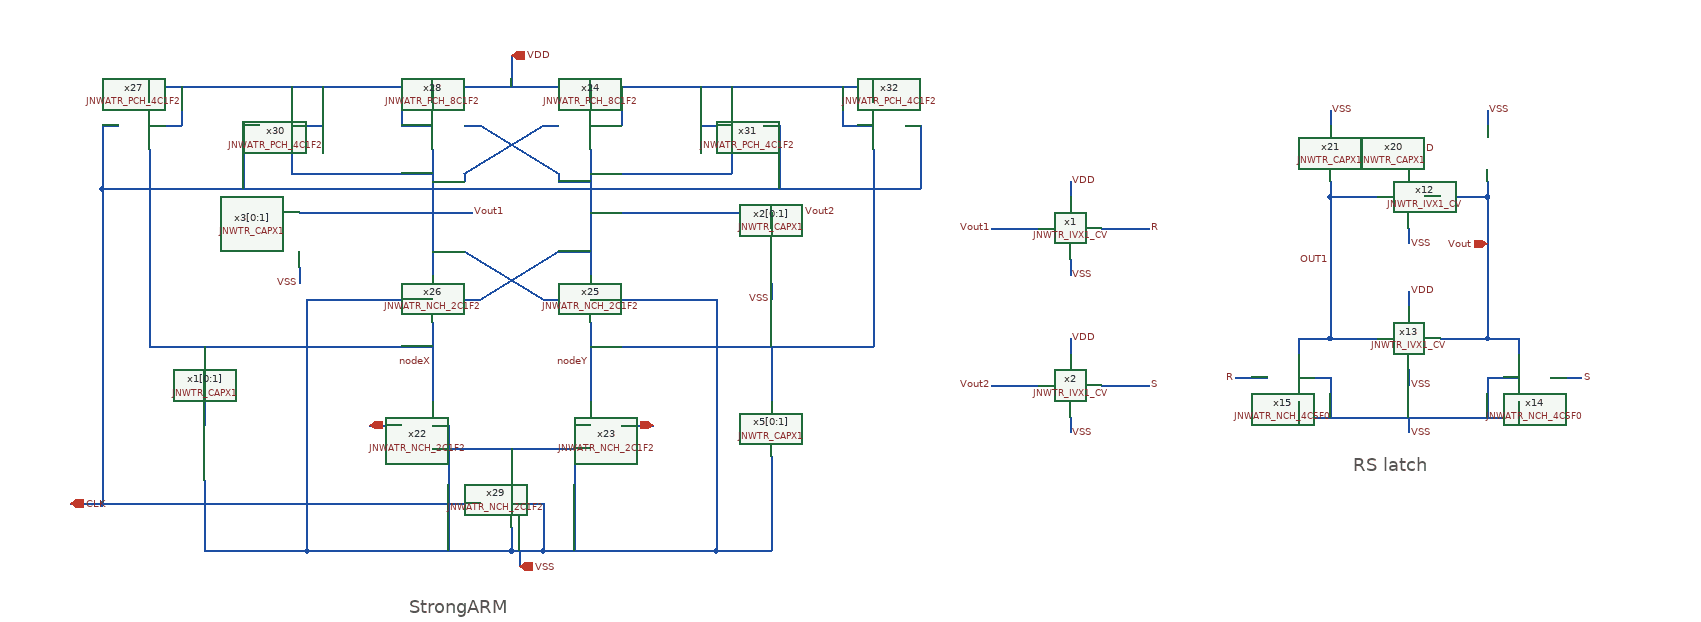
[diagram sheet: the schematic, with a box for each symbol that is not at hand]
v {xschem version=3.4.6 file_version=1.2}
G {}
K {}
V {}
S {}
E {}
T {RS latch} 1920 -420 0 0 0.7 0.7 {}
T {StrongARM} 720 -240 0 0 0.7 0.7 {}
N 1990 -710 1990 -690 {lab=VSS}
N 1990 -630 1990 -610 {lab=VDD}
N 1990 -530 1990 -510 {lab=VSS}
N 1990 -810 1990 -790 {lab=VDD}
N 1890 -570 1950 -570 {lab=OUT1}
N 1890 -750 1890 -570 {lab=OUT1}
N 1890 -750 1950 -750 {lab=OUT1}
N 2030 -750 2090 -750 {lab=Vout}
N 2090 -750 2090 -570 {lab=Vout}
N 2030 -570 2090 -570 {lab=Vout}
N 2090 -570 2130 -570 {lab=Vout}
N 2130 -570 2130 -550 {lab=Vout}
N 1850 -570 1890 -570 {lab=OUT1}
N 1850 -570 1850 -550 {lab=OUT1}
N 1770 -520 1810 -520 {lab=R}
N 2170 -520 2210 -520 {lab=S}
N 2130 -490 2130 -470 {lab=VSS}
N 1850 -470 2130 -470 {lab=VSS}
N 1850 -490 1850 -470 {lab=VSS}
N 1850 -520 1890 -520 {lab=VSS}
N 1890 -520 1890 -470 {lab=VSS}
N 2090 -520 2130 -520 {lab=VSS}
N 2090 -520 2090 -470 {lab=VSS}
N 1990 -470 1990 -450 {lab=VSS}
N 2090 -770 2090 -750 {lab=Vout}
N 1890 -770 1890 -750 {lab=OUT1}
N 2090 -860 2090 -840 {lab=VSS}
N 1890 -860 1890 -840 {lab=VSS}
N 950 -590 950 -490 {lab=nodeY}
N 750 -590 750 -490 {lab=nodeX}
N 750 -810 750 -650 {lab=Vout1}
N 950 -810 950 -650 {lab=Vout2}
N 750 -430 950 -430 {lab=#net1}
N 790 -620 810 -620 {lab=Vout2}
N 810 -620 910 -680 {lab=Vout2}
N 910 -680 950 -680 {lab=Vout2}
N 890 -620 910 -620 {lab=Vout1}
N 790 -680 890 -620 {lab=Vout1}
N 750 -680 790 -680 {lab=Vout1}
N 790 -840 810 -840 {lab=Vout2}
N 810 -840 910 -780 {lab=Vout2}
N 910 -770 950 -770 {lab=Vout2}
N 890 -840 910 -840 {lab=Vout1}
N 790 -780 890 -840 {lab=Vout1}
N 750 -770 790 -770 {lab=Vout1}
N 570 -780 750 -780 {lab=Vout1}
N 570 -810 570 -780 {lab=Vout1}
N 950 -780 1130 -780 {lab=Vout2}
N 1130 -810 1130 -780 {lab=Vout2}
N 950 -560 1310 -560 {lab=nodeY}
N 1310 -810 1310 -560 {lab=nodeY}
N 390 -810 390 -560 {lab=nodeX}
N 390 -560 750 -560 {lab=nodeX}
N 390 -890 390 -870 {lab=VDD}
N 390 -890 1310 -890 {lab=VDD}
N 1310 -890 1310 -880 {lab=VDD}
N 1310 -880 1310 -870 {lab=VDD}
N 1130 -890 1130 -870 {lab=VDD}
N 950 -890 950 -870 {lab=VDD}
N 750 -890 750 -870 {lab=VDD}
N 570 -890 570 -870 {lab=VDD}
N 570 -840 610 -840 {lab=VDD}
N 610 -890 610 -840 {lab=VDD}
N 390 -840 430 -840 {lab=VDD}
N 430 -890 430 -840 {lab=VDD}
N 710 -840 750 -840 {lab=VDD}
N 710 -890 710 -840 {lab=VDD}
N 950 -840 990 -840 {lab=VDD}
N 990 -890 990 -840 {lab=VDD}
N 1090 -840 1130 -840 {lab=VDD}
N 1090 -890 1090 -840 {lab=VDD}
N 1270 -840 1310 -840 {lab=VDD}
N 1270 -890 1270 -840 {lab=VDD}
N 850 -430 850 -390 {lab=#net1}
N 850 -330 850 -300 {lab=VSS}
N 850 -360 890 -360 {lab=VSS}
N 890 -360 890 -300 {lab=VSS}
N 850 -300 890 -300 {lab=VSS}
N 860 -300 860 -280 {lab=VSS}
N 850 -930 850 -890 {lab=VDD}
N 750 -730 800 -730 {lab=Vout1}
N 950 -730 1000 -730 {lab=Vout2}
N 670 -460 710 -460 {lab=Vin1}
N 990 -460 1030 -460 {lab=Vin2}
N 510 -840 530 -840 {lab=CLK}
N 510 -840 510 -760 {lab=CLK}
N 1170 -840 1190 -840 {lab=CLK}
N 1190 -840 1190 -760 {lab=CLK}
N 1350 -840 1370 -840 {lab=CLK}
N 1370 -840 1370 -760 {lab=CLK}
N 430 -760 1370 -760 {lab=CLK}
N 330 -840 350 -840 {lab=CLK}
N 330 -840 330 -760 {lab=CLK}
N 330 -760 430 -760 {lab=CLK}
N 330 -760 330 -360 {lab=CLK}
N 290 -360 330 -360 {lab=CLK}
N 950 -620 1110 -620 {lab=VSS}
N 1110 -620 1110 -300 {lab=VSS}
N 890 -300 1110 -300 {lab=VSS}
N 590 -620 750 -620 {lab=VSS}
N 590 -620 590 -300 {lab=VSS}
N 590 -300 850 -300 {lab=VSS}
N 750 -460 770 -460 {lab=VSS}
N 770 -460 770 -300 {lab=VSS}
N 930 -460 950 -460 {lab=VSS}
N 930 -460 930 -300 {lab=VSS}
N 330 -360 810 -360 {lab=CLK}
N 790 -780 790 -770 {lab=Vout1}
N 910 -780 910 -770 {lab=Vout2}
N 1180 -420 1180 -300 {lab=VSS}
N 1110 -300 1180 -300 {lab=VSS}
N 1180 -560 1180 -490 {lab=nodeY}
N 460 -390 460 -300 {lab=VSS}
N 460 -300 590 -300 {lab=VSS}
N 460 -560 460 -460 {lab=nodeX}
N 1000 -730 1220 -730 {lab=Vout2}
N 1180 -730 1180 -710 {lab=Vout2}
N 1180 -640 1180 -620 {lab=VSS}
N 580 -660 580 -640 {lab=VSS}
N 580 -730 750 -730 {lab=Vout1}
N 1560 -670 1560 -650 {lab=VSS}
N 1560 -770 1560 -750 {lab=VDD}
N 1560 -470 1560 -450 {lab=VSS}
N 1560 -570 1560 -550 {lab=VDD}
N 1460 -710 1520 -710 {lab=Vout1}
N 1600 -710 1660 -710 {lab=R}
N 1460 -510 1520 -510 {lab=Vout2}
N 1600 -510 1660 -510 {lab=#net2}
C {devices/opin.sym} 2090 -690 2 1 {name=p7 lab=Vout
}
C {devices/lab_pin.sym} 1460 -710 0 0 {name=p29 sig_type=std_logic lab=Vout1}
C {devices/lab_pin.sym} 1660 -710 0 1 {name=p30 sig_type=std_logic lab=R}
C {devices/lab_pin.sym} 1460 -510 0 0 {name=p33 sig_type=std_logic lab=Vout2}
C {devices/lab_pin.sym} 1660 -510 0 1 {name=p34 sig_type=std_logic lab=S}
C {JNW_TR_SKY130A/JNWTR_IVX1_CV.sym} 1950 -750 0 0 {name=x12 }
C {JNW_TR_SKY130A/JNWTR_IVX1_CV.sym} 2030 -570 0 1 {name=x13 }
C {devices/lab_pin.sym} 1990 -510 0 1 {name=p18 sig_type=std_logic lab=VSS}
C {devices/lab_pin.sym} 1990 -690 0 1 {name=p19 sig_type=std_logic lab=VSS}
C {devices/lab_pin.sym} 1990 -630 0 1 {name=p20 sig_type=std_logic lab=VDD}
C {devices/lab_pin.sym} 1990 -810 0 1 {name=p21 sig_type=std_logic lab=VDD}
C {JNW_ATR_SKY130A/JNWATR_NCH_4C5F0.sym} 2170 -520 0 1 {name=x14 }
C {JNW_ATR_SKY130A/JNWATR_NCH_4C5F0.sym} 1810 -520 0 0 {name=x15 }
C {devices/lab_pin.sym} 1990 -450 0 1 {name=p22 sig_type=std_logic lab=VSS}
C {devices/lab_pin.sym} 2210 -520 0 1 {name=p23 sig_type=std_logic lab=S}
C {devices/lab_pin.sym} 1770 -520 0 0 {name=p24 sig_type=std_logic lab=R}
C {devices/lab_pin.sym} 1890 -670 0 0 {name=p26 sig_type=std_logic lab=OUT1}
C {JNW_TR_SKY130A/JNWTR_CAPX1.sym} 2090 -780 0 0 {name=x20 }
C {JNW_TR_SKY130A/JNWTR_CAPX1.sym} 1890 -780 0 1 {name=x21 }
C {devices/lab_pin.sym} 1890 -860 0 1 {name=p35 sig_type=std_logic lab=VSS}
C {devices/lab_pin.sym} 2090 -860 0 1 {name=p36 sig_type=std_logic lab=VSS}
C {devices/lab_pin.sym} 800 -730 0 1 {name=p3 sig_type=std_logic lab=Vout1}
C {devices/lab_pin.sym} 1220 -730 0 1 {name=p25 sig_type=std_logic lab=Vout2}
C {devices/ipin.sym} 850 -930 2 1 {name=p37 lab=VDD
}
C {devices/ipin.sym} 860 -280 2 1 {name=p38 lab=VSS

}
C {devices/ipin.sym} 670 -460 2 1 {name=p40 lab=Vin1

}
C {devices/ipin.sym} 1030 -460 2 0 {name=p41 lab=Vin2

}
C {devices/ipin.sym} 290 -360 2 1 {name=p42 lab=CLK

}
C {JNW_ATR_SKY130A/JNWATR_NCH_2C1F2.sym} 710 -460 0 0 {name=x22}
C {JNW_ATR_SKY130A/JNWATR_NCH_2C1F2.sym} 990 -460 0 1 {name=x23}
C {JNW_ATR_SKY130A/JNWATR_PCH_8C1F2.sym} 910 -840 0 0 {name=x24 }
C {JNW_ATR_SKY130A/JNWATR_NCH_2C1F2.sym} 910 -620 0 0 {name=x25 }
C {JNW_ATR_SKY130A/JNWATR_NCH_2C1F2.sym} 790 -620 0 1 {name=x26 }
C {JNW_ATR_SKY130A/JNWATR_PCH_4C1F2.sym} 350 -840 0 0 {name=x27 }
C {JNW_ATR_SKY130A/JNWATR_PCH_8C1F2.sym} 790 -840 0 1 {name=x28 }
C {JNW_ATR_SKY130A/JNWATR_NCH_2C1F2.sym} 810 -360 0 0 {name=x29 }
C {devices/lab_pin.sym} 750 -540 0 0 {name=p44 sig_type=std_logic lab=nodeX}
C {devices/lab_pin.sym} 950 -540 0 0 {name=p45 sig_type=std_logic lab=nodeY}
C {JNW_ATR_SKY130A/JNWATR_PCH_4C1F2.sym} 530 -840 0 0 {name=x30 }
C {JNW_ATR_SKY130A/JNWATR_PCH_4C1F2.sym} 1170 -840 0 1 {name=x31 }
C {JNW_ATR_SKY130A/JNWATR_PCH_4C1F2.sym} 1350 -840 0 1 {name=x32 }
C {JNW_TR_SKY130A/JNWTR_CAPX1.sym} 1180 -430 0 0 {name=x5[0:1]}
C {JNW_TR_SKY130A/JNWTR_CAPX1.sym} 460 -400 0 0 {name=x1[0:1]}
C {JNW_TR_SKY130A/JNWTR_CAPX1.sym} 1180 -650 0 0 {name=x2[0:1]}
C {devices/lab_pin.sym} 1180 -620 0 0 {name=p46 sig_type=std_logic lab=VSS}
C {JNW_TR_SKY130A/JNWTR_CAPX1.sym} 580 -670 0 0 {name=x3[0:1]}
C {devices/lab_pin.sym} 580 -640 0 0 {name=p47 sig_type=std_logic lab=VSS}
C {JNW_TR_SKY130A/JNWTR_IVX1_CV.sym} 1520 -710 0 0 {name=x1 }
C {devices/lab_pin.sym} 1560 -650 0 1 {name=p1 sig_type=std_logic lab=VSS}
C {devices/lab_pin.sym} 1560 -770 0 1 {name=p2 sig_type=std_logic lab=VDD}
C {JNW_TR_SKY130A/JNWTR_IVX1_CV.sym} 1520 -510 0 0 {name=x2 }
C {devices/lab_pin.sym} 1560 -450 0 1 {name=p4 sig_type=std_logic lab=VSS}
C {devices/lab_pin.sym} 1560 -570 0 1 {name=p5 sig_type=std_logic lab=VDD}
